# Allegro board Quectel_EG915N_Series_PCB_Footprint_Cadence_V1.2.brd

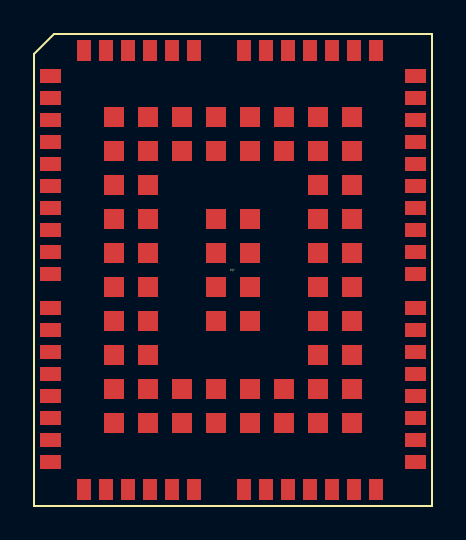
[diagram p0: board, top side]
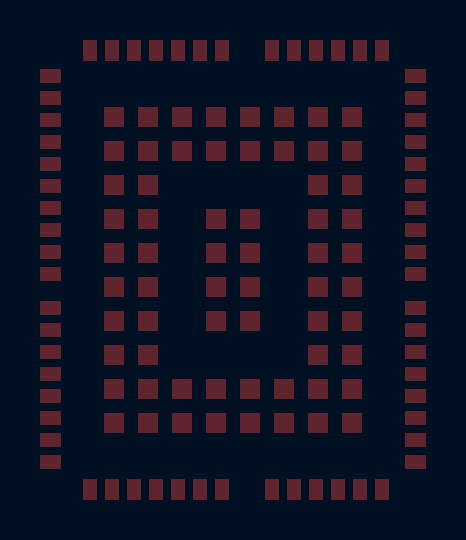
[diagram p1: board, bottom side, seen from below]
No outline. copper layers: TOP, BOTTOM. Coordinates in mm from the lowest, leftmost part position.

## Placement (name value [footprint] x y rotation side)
REF  -  [unnamed]  0 0 0 top

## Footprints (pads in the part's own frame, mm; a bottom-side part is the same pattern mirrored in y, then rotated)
unnamed
  rect 1.05x0.7 smd: 1(-9.125,9.7) 2(-9.125,8.6) 3(-9.125,7.5) 4(-9.125,6.4) 5(-9.125,5.3) 6(-9.125,4.2) 7(-9.125,3.1) 8(-9.125,2) 9(-9.125,0.9) 10(-9.125,-0.2) 11(-9.125,-1.9) 12(-9.125,-3) 13(-9.125,-4.1) 14(-9.125,-5.2) 15(-9.125,-6.3) 16(-9.125,-7.4) 17(-9.125,-8.5) 18(-9.125,-9.6) 32(9.125,-9.6) 33(9.125,-8.5) 34(9.125,-7.4) 35(9.125,-6.3) 36(9.125,-5.2) 37(9.125,-4.1) 38(9.125,-3) 39(9.125,-1.9) 40(9.125,-0.2) 41(9.125,0.9) 42(9.125,2) 43(9.125,3.1) 44(9.125,4.2) 45(9.125,5.3) 46(9.125,6.4) 47(9.125,7.5) 48(9.125,8.6) 49(9.125,9.7)
  rect 0.7x1.05 smd: 19(-7.45,-10.975) 20(-6.35,-10.975) 21(-5.25,-10.975) 22(-4.15,-10.975) 23(-3.05,-10.975) 24(-1.95,-10.975) 25(0.55,-10.975) 26(1.65,-10.975) 27(2.75,-10.975) 28(3.85,-10.975) 29(4.95,-10.975) 30(6.05,-10.975) 31(7.15,-10.975) 50(7.15,10.975) 51(6.05,10.975) 52(4.95,10.975) 53(3.85,10.975) 54(2.75,10.975) 55(1.65,10.975) 56(0.55,10.975) 57(-1.95,10.975) 58(-3.05,10.975) 59(-4.15,10.975) 60(-5.25,10.975) 61(-6.35,10.975) 62(-7.45,10.975)
  rect 1x1 smd: 63(-5.95,4.25) 64(-5.95,2.55) 65(-5.95,0.85) 66(-5.95,-0.85) 67(-5.95,-2.55) 68(-5.95,-4.25) 69(-2.55,-7.65) 70(-0.85,-7.65) 71(0.85,-7.65) 72(2.55,-7.65) 73(5.95,-4.25) 74(5.95,-2.55) 75(5.95,-0.85) 76(5.95,0.85) 77(5.95,2.55) 78(5.95,4.25) 79(2.55,7.65) 80(0.85,7.65) 81(-0.85,7.65) 82(-2.55,7.65) 83(-4.25,4.25) 84(-4.25,2.55) 85(-4.25,0.85) 86(-4.25,-0.85) 87(-4.25,-2.55) 88(-4.25,-4.25) 89(-2.55,-5.95) 90(-0.85,-5.95) 91(0.85,-5.95) 92(2.55,-5.95) 93(4.25,-4.25) 94(4.25,-2.55) 95(4.25,-0.85) 96(4.25,0.85) 97(4.25,2.55) 98(4.25,4.25) 99(2.55,5.95) 100(0.85,5.95) 101(-0.85,5.95) 102(-2.55,5.95) 103(-5.95,7.65) 104(-5.95,5.95) 105(-5.95,-5.95) 106(-5.95,-7.65) 107(-4.25,-7.65) 108(4.25,-7.65) 109(5.95,-7.65) 110(5.95,-5.95) 111(5.95,5.95) 112(5.95,7.65) 113(4.25,7.65) 114(-4.25,7.65) 115(-4.25,5.95) 116(-4.25,-5.95) 117(4.25,-5.95) 118(4.25,5.95) 119(-0.85,2.55) 120(-0.85,0.85) 121(-0.85,-0.85) 122(-0.85,-2.55) 123(0.85,-2.55) 124(0.85,-0.85) 125(0.85,0.85) 126(0.85,2.55)

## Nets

Pads without a net: REF 1 2 3 4 5 6 7 8 9 10 11 12 13 14 15 16 17 18 19 20 21 22 23 24 25 26 27 28 29 30 31 32 33 34 35 36 37 38 39 40 41 42 43 44 45 46 47 48 49 50 51 52 53 54 55 56 57 58 59 60 61 62 63 64 65 66 67 68 69 70 71 72 73 74 75 76 77 78 79 80 81 82 83 84 85 86 87 88 89 90 91 92 93 94 95 96 97 98 99 100 101 102 103 104 105 106 107 108 109 110 111 112 113 114 115 116 117 118 119 120 121 122 123 124 125 126
